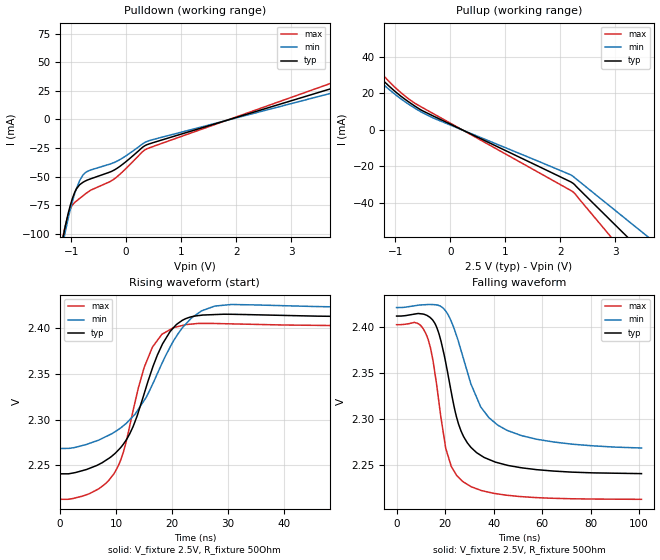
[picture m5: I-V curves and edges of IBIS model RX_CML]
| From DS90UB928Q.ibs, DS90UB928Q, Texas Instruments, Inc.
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|   Model
[Model]   RX_CML
Model_type   Output
Polarity   Non-Inverting
Vmeas = 2.4
Vref = 2.5
Cref = 1pF
Rref = 50
|   typ   min   max
C_comp   0.9027pF   0.8382pF   0.9749pF
[Voltage Range]   3.3   3.0   3.6
[Temperature Range]   25   105   -40
[Pullup Reference]   2.5   2.4999   2.5001 | the driver power is regulated at 2.5V
[Pulldown Reference]   0   0   0
[Power Clamp Reference]   2.5   2.4999   2.5001
[GND Clamp Reference]   0   0   0
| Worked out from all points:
|   slope of the pulldown table from 0 to 0.375 V, typ, clamps not added: 25.6 ohm
|   slope of the pullup table from 0 to 0.375 V, typ, clamps not added: 69.5 ohm
|   falling waveform, V_fixture 2.5V, R_fixture 50Ohm: 20-80 % time 10.1ns typ, 14.4ns min, 7.35ns max; typ from 2.41 V to 2.24 V
|   rising waveform, V_fixture 2.5V, R_fixture 50Ohm: 20-80 % time 6.4ns typ, 8.4ns min, 5.03ns max; typ from 2.24 V to 2.41 V
[Pulldown]
|   Voltage   I(typ)   I(min)   I(max)
-3.3V     -668.6mA   -646.3mA   -687.3mA
-1.171V   -109.4mA   -113.8mA   -108mA
-1.119V   -96.46mA   -101.2mA   -95.62mA
-1.104V   -92.99mA   -97.74mA   -92.48mA
-1.021V   -76.29mA   -80mA      -79.04mA
-931.3mV  -63.41mA   -64.41mA   -72.59mA
-848.8mV  -57.38mA   -53.95mA   -69.28mA
-781.2mV  -54.96mA   -48.49mA   -66.73mA
-646.2mV  -52.03mA   -44.3mA    -61.97mA
-207.5mV  -44.06mA   -37.52mA   -51.79mA
370mV     -22.34mA   -19.5mA    -25.94mA
6.6V      68.84mA    58.87mA    80.81mA
[Pullup]
|   Voltage   I(typ)   I(min)   I(max)
-3.3V     86.96mA    79.21mA    97.66mA
-2.92V    75.99mA    69.27mA    85.26mA
-1.126V   24.2mA     22.37mA    26.76mA
-905mV    18.5mA     17.07mA    20.46mA
-766.2mV  15.43mA    14.12mA    17.07mA
-548.7mV  11.1mA     10.06mA    12.84mA
-312.5mV  7.546mA    6.451mA    8.863mA
2.215V    -28.98mA   -25.15mA   -33.7mA
2.275V    -30.53mA   -26.59mA   -35.26mA
2.496V    -37.19mA   -31.97mA   -43.4mA
5.1V      -114.6mA   -95.19mA   -137.1mA
6.6V      -159.2mA   -131.6mA   -191mA
[Ramp]
R_load = 50
|   typ   min   max
dV/dt_r   0.102377/6.39909e-09   0.091258/8.39841e-09   0.113483/5.02004e-09
dV/dt_f   0.102377/1.00609e-08   0.091258/1.44314e-08   0.113483/7.3518e-09
[Falling Waveform]
V_fixture = 2.5V
V_fixture_min = 2.5V
V_fixture_max = 2.5V
R_fixture = 50Ohm
C_fixture = 0F
|   Time   V(typ)   V(min)   V(max)
0s        2.411V     2.421V     2.402V
10.67ns   2.414V     2.424V     2.399V
13.05ns   2.411V     2.424V     2.386V
15.68ns   2.404V     2.424V     2.352V
20.28ns   2.361V     2.417V     2.268V
24.09ns   2.309V     2.395V     2.242V
27.14ns   2.284V     2.369V     2.232V
34.68ns   2.261V     2.313V     2.223V
45.67ns   2.25V      2.287V     2.217V
101ns     2.241V     2.268V     2.213V
[Rising Waveform]
V_fixture = 2.5V
V_fixture_min = 2.5V
V_fixture_max = 2.5V
R_fixture = 50Ohm
C_fixture = 0F
|   Time   V(typ)   V(min)   V(max)
0s        2.241V     2.268V     2.213V
5.242ns   2.247V     2.274V     2.219V
9.613ns   2.262V     2.286V     2.241V
11.35ns   2.274V     2.293V     2.265V
15.05ns   2.329V     2.321V     2.357V
18.2ns    2.381V     2.361V     2.393V
20.28ns   2.4V       2.386V     2.401V
25.29ns   2.414V     2.419V     2.405V
30.64ns   2.415V     2.426V     2.405V
101ns     2.411V     2.421V     2.402V
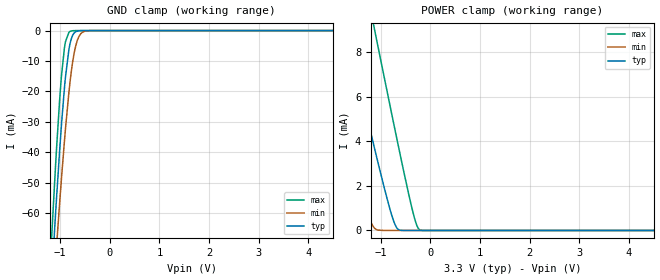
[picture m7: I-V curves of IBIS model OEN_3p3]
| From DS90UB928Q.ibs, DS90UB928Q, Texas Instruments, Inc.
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|   Model
[Model]   OEN_3p3
Model_type   Input
Vinl = 0.8
Vinh = 2.0
|   typ   min   max
C_comp   0.8244pF   0.7669pF   0.8760pF
[Voltage Range]   3.3   3   3.6
[Temperature Range]   25   105   -40
[Power Clamp Reference]   3.3   3   3.6
[GND Clamp Reference]   0   0   0
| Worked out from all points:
|   GND clamp passes 1 mA (typ) near -0.73 V on its own axis
|   POWER clamp passes 1 mA (typ) near -0.82 V on its own axis
[GND Clamp]
|   Voltage   I(typ)   I(min)   I(max)
-3.3V     -713.1mA   -643.8mA   -777mA
-1.181V   -84.12mA   -96.62mA   -70.54mA
-1.092V   -59.89mA   -75.21mA   -43.99mA
-1.073V   -54.72mA   -70.58mA   -38.47mA
-1.013V   -39.91mA   -57.05mA   -23.26mA
-973.5mV  -30.79mA   -48.42mA   -14.73mA
-894.3mV  -15.34mA   -32.41mA   -3.698mA
-795.3mV  -3.862mA   -16mA      -232.2uA
-726mV    -947.7uA   -8.051mA   -24.15uA
-656.7mV  -172.7uA   -3.327mA   -5.411uA
-478.5mV  -2.087uA   -124.9uA   -554.7nA
6.59V     0A         0A         0A
[POWER Clamp]
|   Voltage   I(typ)   I(min)   I(max)
-3.3V     24.72mA    17.34mA    33.27mA
-2.518V   17.07mA    10.75mA    24.5mA
-2.251V   14.46mA    8.521mA    21.51mA
-1.716V   9.284mA    4.13mA     15.55mA
-1.27V    5.03mA     771.6uA    10.6mA
-1.122V   3.642mA    92.22uA    8.965mA
-1.082V   3.277mA    34.08uA    8.53mA
-825mV    1.025mA    494.2nA    5.713mA
-686.4mV  147.3uA    394nA      4.217mA
-349.8mV  480.5nA    222.4nA    794.8uA
-211.2mV  369.6nA    168.2nA    24.78uA
6.59V     0A         0A         0A
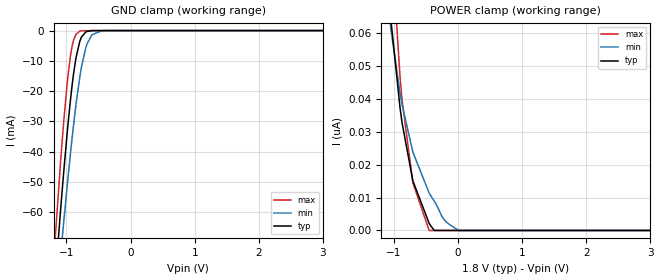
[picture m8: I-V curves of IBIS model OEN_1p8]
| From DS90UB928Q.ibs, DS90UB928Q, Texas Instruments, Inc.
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|   Model
[Model]   OEN_1p8
Model_type   Input
Vinl = 0.63
Vinh = 1.17
|   typ   min   max
C_comp   0.8244pF   0.7669pF   0.8760pF
[Voltage Range]   1.8   1.71   1.89
[Temperature Range]   25   105   -40
[Power Clamp Reference]   1.8   1.71   1.89
[GND Clamp Reference]   0   0   -0
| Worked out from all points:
|   GND clamp passes 1 mA (typ) near -0.72 V on its own axis
[GND Clamp]
|   Voltage   I(typ)   I(min)   I(max)
-1.8V     -268.1mA   -256.4mA   -277.3mA
-1.211V   -92.55mA   -104mA     -79.92mA
-1.087V   -58.55mA   -74.01mA   -42.56mA
-1.055V   -50.19mA   -66.49mA   -33.71mA
-984.6mV  -33.28mA   -50.8mA    -16.95mA
-925.2mV  -20.83mA   -38.42mA   -6.927mA
-849.6mV  -8.947mA   -24.38mA   -1.201mA
-790.2mV  -3.53mA    -15.31mA   -196.8uA
-676.8mV  -292.1uA   -4.397mA   -7.397uA
-601.2mV  -40.63uA   -1.389mA   -3.01uA
-450mV    -1.39uA    -66.56uA   -306.1nA
3.595V    0A         0A         0A
[POWER Clamp]
|   Voltage   I(typ)   I(min)   I(max)
-1.8V     450.4nA    311.2nA    840.5nA
-1.049V   64.59nA    61.73nA    91.21nA
-903.6mV  37.31nA    41.79nA    46.75nA
-871.2mV  32.67nA    38.23nA    39.6nA
-703.8mV  15.08nA    23.84nA    14.47nA
-450mV    2.157nA    11.39nA    0A
-369mV    41.6pA     8.873nA    0A
-255.6mV  0A         4.479nA    0A
-217.8mV  0A         3.34nA     0A
-136.8mV  0A         1.877nA    0A
14.4mV    0A         0A         0A
3.595V    0A         0A         0A
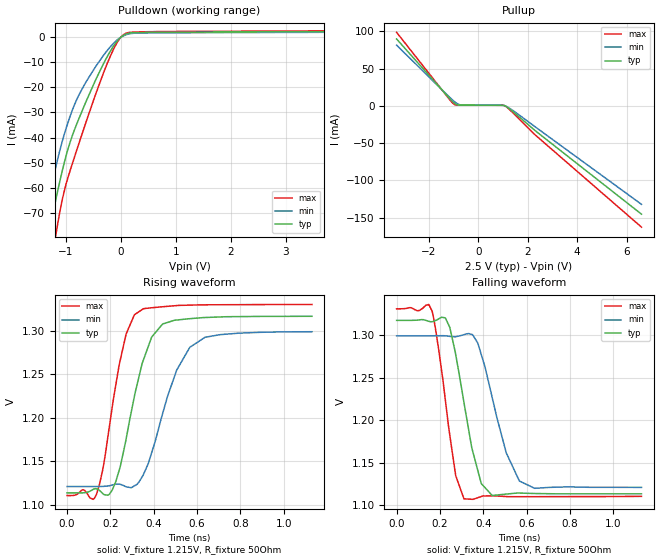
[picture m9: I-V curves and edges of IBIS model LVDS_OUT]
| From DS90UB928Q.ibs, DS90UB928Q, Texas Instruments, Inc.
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|   Model
[Model]   LVDS_OUT
Model_type   Output
Polarity   Non-Inverting
Vmeas = 1.2
Vref = 1.2
Cref = 1pF
Rref = 50
|   typ   min   max
C_comp   0.3062pF   0.2640pF   0.3274pF
[Voltage Range]   2.5   2.4999   2.5001
[Temperature Range]   25   105   -40
[Pullup Reference]   2.5   2.4999   2.5001
[Pulldown Reference]   0   0   0
[Power Clamp Reference]   2.5   2.4999   2.5001
[GND Clamp Reference]   0   0   0
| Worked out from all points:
|   slope of the pulldown table from 0 to 0.375 V, typ, clamps not added: 196 ohm
|   slope of the pullup table from 0 to 0.375 V, typ, clamps not added: 13 kohm
|   falling waveform, V_fixture 1.215V, R_fixture 50Ohm: 20-80 % time 87.7ps typ, 108ps min, 69.5ps max; typ from 1.32 V to 1.11 V
|   rising waveform, V_fixture 1.215V, R_fixture 50Ohm: 20-80 % time 112ps typ, 139ps min, 89.1ps max; typ from 1.11 V to 1.32 V
[Pulldown]
|   Voltage   I(typ)   I(min)   I(max)
-3.3V     -291.8mA   -259.4mA   -378mA
-1.993V   -151.7mA   -131.3mA   -193.5mA
-1.25V    -72.09mA   -58.46mA   -88.58mA
-1.175V   -64.05mA   -51.11mA   -78mA
-1.16V    -62.52mA   -49.71mA   -76mA
-1.066V   -53.45mA   -41.67mA   -64.9mA
-998.8mV  -47.58mA   -36.64mA   -58.81mA
-762.5mV  -32.54mA   -23.09mA   -42.45mA
-207.5mV  -6.283mA   -4.335mA   -8.518mA
-31.25mV  -745.4uA   -538.5uA   -993.4uA
103.7mV   1.287mA    981.6uA    1.599mA
6.6V      2.366mA    2.084mA    2.705mA
[Pullup]
|   Voltage   I(typ)   I(min)   I(max)
-3.3V     89.77mA    81.47mA    98.69mA
-1.119V   8.585mA    10.37mA    6.848mA
-987.5mV  4.291mA    6.437mA    2.419mA
-848.8mV  1.42mA     2.995mA    1.046mA
-668.7mV  1.003mA    1.081mA    994.8uA
973.8mV   790.7uA    781.8uA    781uA
1.101V    -294.2uA   -146.3uA   -428.5uA
1.42V     -8.176mA   -6.629mA   -9.927mA
2.339V    -34.22mA   -29.01mA   -40.04mA
6.6V      -145.4mA   -132.2mA   -162.7mA
[Ramp]
R_load = 50
|   typ   min   max
dV/dt_r   0.122154/1.11676e-10   0.107063/1.39269e-10   0.132146/8.91501e-11
dV/dt_f   0.122546/8.76852e-11   0.107063/1.08223e-10   0.132504/6.95064e-11
[Falling Waveform]
V_fixture = 1.215V
V_fixture_min = 1.207V
V_fixture_max = 1.221V
R_fixture = 50Ohm
C_fixture = 0F
|   Time   V(typ)   V(min)   V(max)
0s        1.317V     1.299V     1.331V
164ps     1.316V     1.299V     1.328V
245.5ps   1.309V     1.299V     1.182V
272.8ps   1.277V     1.298V     1.135V
310.9ps   1.221V     1.301V     1.107V
350.7ps   1.164V     1.301V     1.107V
390.7ps   1.125V     1.277V     1.11V
505.9ps   1.113V     1.161V     1.11V
566.5ps   1.114V     1.128V     1.11V
1.13ns    1.113V     1.121V     1.11V
[Rising Waveform]
V_fixture = 1.215V
V_fixture_min = 1.207V
V_fixture_max = 1.221V
R_fixture = 50Ohm
C_fixture = 0F
|   Time   V(typ)   V(min)   V(max)
0s        1.113V     1.121V     1.11V
135.5ps   1.118V     1.121V     1.112V
168.8ps   1.112V     1.121V     1.146V
224.9ps   1.126V     1.123V     1.238V
272.8ps   1.176V     1.121V     1.297V
310.9ps   1.225V     1.122V     1.319V
390.7ps   1.293V     1.16V      1.327V
505.9ps   1.313V     1.255V     1.329V
566.5ps   1.314V     1.281V     1.33V
1.13ns    1.317V     1.299V     1.331V
